VERSION 5.7 ;
  NOWIREEXTENSIONATPIN ON ;
  DIVIDERCHAR "/" ;
  BUSBITCHARS "[]" ;
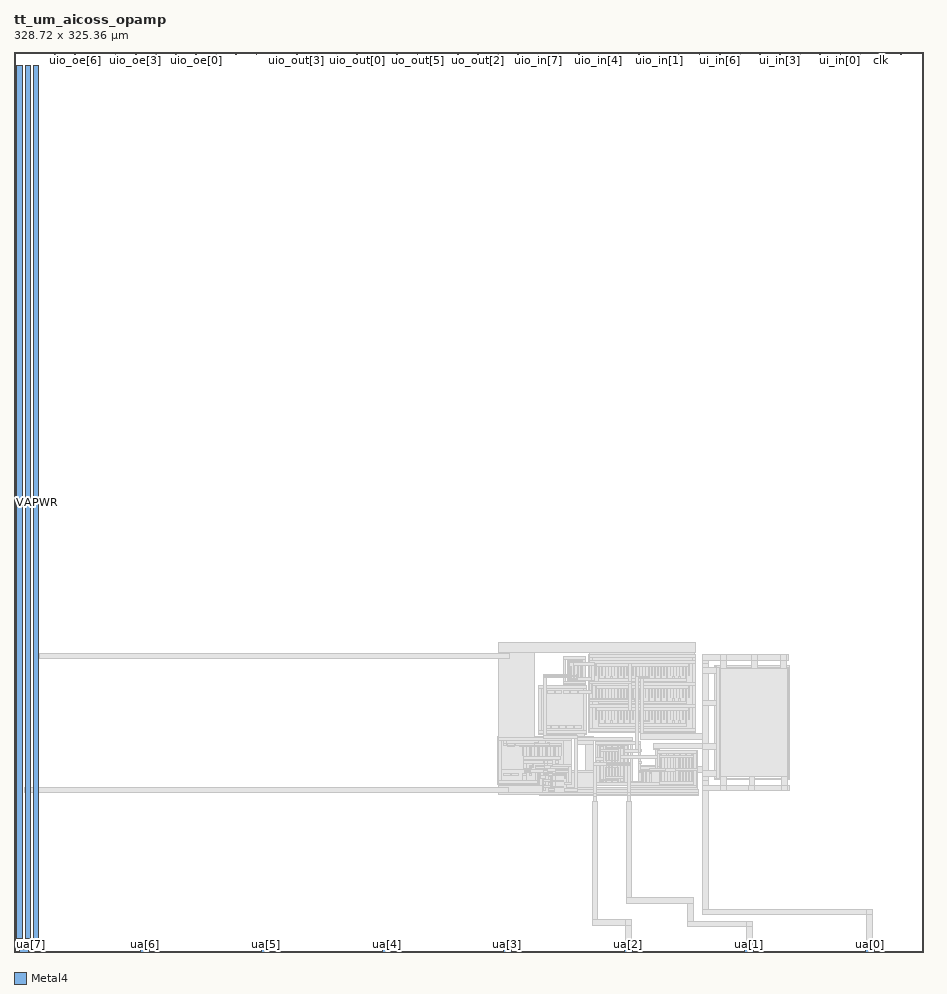
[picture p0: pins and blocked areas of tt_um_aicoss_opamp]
MACRO tt_um_aicoss_opamp
  CLASS BLOCK ;
  FOREIGN tt_um_aicoss_opamp ;
  ORIGIN 0.000 0.000 ;
  SIZE 328.720 BY 325.360 ;
  PIN clk
    DIRECTION INPUT ;
    USE SIGNAL ;
    PORT
      LAYER Metal4 ;
        RECT 313.170 324.360 313.470 325.360 ;
    END
  END clk
  PIN ena
    DIRECTION INPUT ;
    USE SIGNAL ;
    PORT
      LAYER Metal4 ;
        RECT 320.450 324.360 320.750 325.360 ;
    END
  END ena
  PIN rst_n
    DIRECTION INPUT ;
    USE SIGNAL ;
    PORT
      LAYER Metal4 ;
        RECT 305.890 324.360 306.190 325.360 ;
    END
  END rst_n
  PIN ua[0]
    DIRECTION INOUT ;
    USE SIGNAL ;
    ANTENNADIFFAREA 79.559998 ;
    PORT
      LAYER Metal4 ;
        RECT 307.900 0.000 310.900 1.000 ;
    END
  END ua[0]
  PIN ua[1]
    DIRECTION INOUT ;
    USE SIGNAL ;
    ANTENNAGATEAREA 7.200000 ;
    PORT
      LAYER Metal4 ;
        RECT 264.220 0.000 267.220 1.000 ;
    END
  END ua[1]
  PIN ua[2]
    DIRECTION INOUT ;
    USE SIGNAL ;
    ANTENNAGATEAREA 7.200000 ;
    PORT
      LAYER Metal4 ;
        RECT 220.540 0.000 223.540 1.000 ;
    END
  END ua[2]
  PIN ua[3]
    DIRECTION INOUT ;
    USE SIGNAL ;
    PORT
      LAYER Metal4 ;
        RECT 176.860 0.000 179.860 1.000 ;
    END
  END ua[3]
  PIN ua[4]
    DIRECTION INOUT ;
    USE SIGNAL ;
    PORT
      LAYER Metal4 ;
        RECT 133.180 0.000 136.180 1.000 ;
    END
  END ua[4]
  PIN ua[5]
    DIRECTION INOUT ;
    USE SIGNAL ;
    PORT
      LAYER Metal4 ;
        RECT 89.500 0.000 92.500 1.000 ;
    END
  END ua[5]
  PIN ua[6]
    DIRECTION INOUT ;
    USE SIGNAL ;
    PORT
      LAYER Metal4 ;
        RECT 45.820 0.000 48.820 1.000 ;
    END
  END ua[6]
  PIN ua[7]
    DIRECTION INOUT ;
    USE SIGNAL ;
    PORT
      LAYER Metal4 ;
        RECT 2.140 0.000 5.140 1.000 ;
    END
  END ua[7]
  PIN ui_in[0]
    DIRECTION INPUT ;
    USE SIGNAL ;
    PORT
      LAYER Metal4 ;
        RECT 298.610 324.360 298.910 325.360 ;
    END
  END ui_in[0]
  PIN ui_in[1]
    DIRECTION INPUT ;
    USE SIGNAL ;
    PORT
      LAYER Metal4 ;
        RECT 291.330 324.360 291.630 325.360 ;
    END
  END ui_in[1]
  PIN ui_in[2]
    DIRECTION INPUT ;
    USE SIGNAL ;
    PORT
      LAYER Metal4 ;
        RECT 284.050 324.360 284.350 325.360 ;
    END
  END ui_in[2]
  PIN ui_in[3]
    DIRECTION INPUT ;
    USE SIGNAL ;
    PORT
      LAYER Metal4 ;
        RECT 276.770 324.360 277.070 325.360 ;
    END
  END ui_in[3]
  PIN ui_in[4]
    DIRECTION INPUT ;
    USE SIGNAL ;
    PORT
      LAYER Metal4 ;
        RECT 269.490 324.360 269.790 325.360 ;
    END
  END ui_in[4]
  PIN ui_in[5]
    DIRECTION INPUT ;
    USE SIGNAL ;
    PORT
      LAYER Metal4 ;
        RECT 262.210 324.360 262.510 325.360 ;
    END
  END ui_in[5]
  PIN ui_in[6]
    DIRECTION INPUT ;
    USE SIGNAL ;
    PORT
      LAYER Metal4 ;
        RECT 254.930 324.360 255.230 325.360 ;
    END
  END ui_in[6]
  PIN ui_in[7]
    DIRECTION INPUT ;
    USE SIGNAL ;
    PORT
      LAYER Metal4 ;
        RECT 247.650 324.360 247.950 325.360 ;
    END
  END ui_in[7]
  PIN uio_in[0]
    DIRECTION INPUT ;
    USE SIGNAL ;
    PORT
      LAYER Metal4 ;
        RECT 240.370 324.360 240.670 325.360 ;
    END
  END uio_in[0]
  PIN uio_in[1]
    DIRECTION INPUT ;
    USE SIGNAL ;
    PORT
      LAYER Metal4 ;
        RECT 233.090 324.360 233.390 325.360 ;
    END
  END uio_in[1]
  PIN uio_in[2]
    DIRECTION INPUT ;
    USE SIGNAL ;
    PORT
      LAYER Metal4 ;
        RECT 225.810 324.360 226.110 325.360 ;
    END
  END uio_in[2]
  PIN uio_in[3]
    DIRECTION INPUT ;
    USE SIGNAL ;
    PORT
      LAYER Metal4 ;
        RECT 218.530 324.360 218.830 325.360 ;
    END
  END uio_in[3]
  PIN uio_in[4]
    DIRECTION INPUT ;
    USE SIGNAL ;
    PORT
      LAYER Metal4 ;
        RECT 211.250 324.360 211.550 325.360 ;
    END
  END uio_in[4]
  PIN uio_in[5]
    DIRECTION INPUT ;
    USE SIGNAL ;
    PORT
      LAYER Metal4 ;
        RECT 203.970 324.360 204.270 325.360 ;
    END
  END uio_in[5]
  PIN uio_in[6]
    DIRECTION INPUT ;
    USE SIGNAL ;
    PORT
      LAYER Metal4 ;
        RECT 196.690 324.360 196.990 325.360 ;
    END
  END uio_in[6]
  PIN uio_in[7]
    DIRECTION INPUT ;
    USE SIGNAL ;
    PORT
      LAYER Metal4 ;
        RECT 189.410 324.360 189.710 325.360 ;
    END
  END uio_in[7]
  PIN uio_oe[0]
    DIRECTION OUTPUT ;
    USE SIGNAL ;
    PORT
      LAYER Metal4 ;
        RECT 65.650 324.360 65.950 325.360 ;
    END
  END uio_oe[0]
  PIN uio_oe[1]
    DIRECTION OUTPUT ;
    USE SIGNAL ;
    PORT
      LAYER Metal4 ;
        RECT 58.370 324.360 58.670 325.360 ;
    END
  END uio_oe[1]
  PIN uio_oe[2]
    DIRECTION OUTPUT ;
    USE SIGNAL ;
    PORT
      LAYER Metal4 ;
        RECT 51.090 324.360 51.390 325.360 ;
    END
  END uio_oe[2]
  PIN uio_oe[3]
    DIRECTION OUTPUT ;
    USE SIGNAL ;
    PORT
      LAYER Metal4 ;
        RECT 43.810 324.360 44.110 325.360 ;
    END
  END uio_oe[3]
  PIN uio_oe[4]
    DIRECTION OUTPUT ;
    USE SIGNAL ;
    PORT
      LAYER Metal4 ;
        RECT 36.530 324.360 36.830 325.360 ;
    END
  END uio_oe[4]
  PIN uio_oe[5]
    DIRECTION OUTPUT ;
    USE SIGNAL ;
    PORT
      LAYER Metal4 ;
        RECT 29.250 324.360 29.550 325.360 ;
    END
  END uio_oe[5]
  PIN uio_oe[6]
    DIRECTION OUTPUT ;
    USE SIGNAL ;
    PORT
      LAYER Metal4 ;
        RECT 21.970 324.360 22.270 325.360 ;
    END
  END uio_oe[6]
  PIN uio_oe[7]
    DIRECTION OUTPUT ;
    USE SIGNAL ;
    PORT
      LAYER Metal4 ;
        RECT 14.690 324.360 14.990 325.360 ;
    END
  END uio_oe[7]
  PIN uio_out[0]
    DIRECTION OUTPUT ;
    USE SIGNAL ;
    PORT
      LAYER Metal4 ;
        RECT 123.890 324.360 124.190 325.360 ;
    END
  END uio_out[0]
  PIN uio_out[1]
    DIRECTION OUTPUT ;
    USE SIGNAL ;
    PORT
      LAYER Metal4 ;
        RECT 116.610 324.360 116.910 325.360 ;
    END
  END uio_out[1]
  PIN uio_out[2]
    DIRECTION OUTPUT ;
    USE SIGNAL ;
    PORT
      LAYER Metal4 ;
        RECT 109.330 324.360 109.630 325.360 ;
    END
  END uio_out[2]
  PIN uio_out[3]
    DIRECTION OUTPUT ;
    USE SIGNAL ;
    PORT
      LAYER Metal4 ;
        RECT 102.050 324.360 102.350 325.360 ;
    END
  END uio_out[3]
  PIN uio_out[4]
    DIRECTION OUTPUT ;
    USE SIGNAL ;
    PORT
      LAYER Metal4 ;
        RECT 94.770 324.360 95.070 325.360 ;
    END
  END uio_out[4]
  PIN uio_out[5]
    DIRECTION OUTPUT ;
    USE SIGNAL ;
    PORT
      LAYER Metal4 ;
        RECT 87.490 324.360 87.790 325.360 ;
    END
  END uio_out[5]
  PIN uio_out[6]
    DIRECTION OUTPUT ;
    USE SIGNAL ;
    PORT
      LAYER Metal4 ;
        RECT 80.210 324.360 80.510 325.360 ;
    END
  END uio_out[6]
  PIN uio_out[7]
    DIRECTION OUTPUT ;
    USE SIGNAL ;
    PORT
      LAYER Metal4 ;
        RECT 72.930 324.360 73.230 325.360 ;
    END
  END uio_out[7]
  PIN uo_out[0]
    DIRECTION OUTPUT ;
    USE SIGNAL ;
    PORT
      LAYER Metal4 ;
        RECT 182.130 324.360 182.430 325.360 ;
    END
  END uo_out[0]
  PIN uo_out[1]
    DIRECTION OUTPUT ;
    USE SIGNAL ;
    PORT
      LAYER Metal4 ;
        RECT 174.850 324.360 175.150 325.360 ;
    END
  END uo_out[1]
  PIN uo_out[2]
    DIRECTION OUTPUT ;
    USE SIGNAL ;
    PORT
      LAYER Metal4 ;
        RECT 167.570 324.360 167.870 325.360 ;
    END
  END uo_out[2]
  PIN uo_out[3]
    DIRECTION OUTPUT ;
    USE SIGNAL ;
    PORT
      LAYER Metal4 ;
        RECT 160.290 324.360 160.590 325.360 ;
    END
  END uo_out[3]
  PIN uo_out[4]
    DIRECTION OUTPUT ;
    USE SIGNAL ;
    PORT
      LAYER Metal4 ;
        RECT 153.010 324.360 153.310 325.360 ;
    END
  END uo_out[4]
  PIN uo_out[5]
    DIRECTION OUTPUT ;
    USE SIGNAL ;
    PORT
      LAYER Metal4 ;
        RECT 145.730 324.360 146.030 325.360 ;
    END
  END uo_out[5]
  PIN uo_out[6]
    DIRECTION OUTPUT ;
    USE SIGNAL ;
    PORT
      LAYER Metal4 ;
        RECT 138.450 324.360 138.750 325.360 ;
    END
  END uo_out[6]
  PIN uo_out[7]
    DIRECTION OUTPUT ;
    USE SIGNAL ;
    PORT
      LAYER Metal4 ;
        RECT 131.170 324.360 131.470 325.360 ;
    END
  END uo_out[7]
  PIN VDPWR
    DIRECTION INOUT ;
    USE POWER ;
    PORT
      LAYER Metal4 ;
        RECT 1.000 5.000 3.000 320.360 ;
    END
  END VDPWR
  PIN VGND
    DIRECTION INOUT ;
    USE GROUND ;
    PORT
      LAYER Metal4 ;
        RECT 4.000 5.000 6.000 320.360 ;
    END
  END VGND
  PIN VAPWR
    DIRECTION INOUT ;
    USE POWER ;
    PORT
      LAYER Metal4 ;
        RECT 7.000 5.000 9.000 320.360 ;
    END
  END VAPWR
  OBS
      LAYER Nwell ;
        RECT 199.980 98.230 204.980 105.380 ;
      LAYER Pwell ;
        RECT 189.500 78.700 207.060 96.480 ;
      LAYER Nwell ;
        RECT 207.800 79.450 246.420 107.560 ;
        RECT 174.950 66.150 200.000 77.750 ;
        RECT 174.950 60.700 189.570 66.150 ;
      LAYER Pwell ;
        RECT 193.950 65.900 200.900 65.950 ;
        RECT 189.950 64.350 200.900 65.900 ;
        RECT 189.950 63.700 201.200 64.350 ;
      LAYER Nwell ;
        RECT 174.950 60.650 189.500 60.700 ;
      LAYER Pwell ;
        RECT 189.950 56.600 200.900 63.700 ;
      LAYER Nwell ;
        RECT 210.330 60.030 222.030 75.730 ;
      LAYER Pwell ;
        RECT 225.650 60.000 231.670 67.270 ;
        RECT 232.200 58.900 246.950 72.900 ;
      LAYER Metal1 ;
        RECT 175.200 108.350 246.200 111.850 ;
        RECT 175.200 77.475 188.250 108.350 ;
        RECT 208.000 107.375 245.900 108.350 ;
        RECT 198.515 105.875 206.615 106.905 ;
        RECT 198.515 97.695 199.545 105.875 ;
        RECT 200.315 104.535 204.765 105.065 ;
        RECT 200.315 99.045 200.845 104.535 ;
        RECT 202.300 104.130 202.800 104.150 ;
        RECT 202.280 103.650 202.800 104.130 ;
        RECT 202.280 103.630 202.780 103.650 ;
        RECT 201.305 100.180 201.535 103.230 ;
        RECT 202.425 100.230 202.655 103.630 ;
        RECT 203.545 100.180 203.775 103.230 ;
        RECT 201.230 99.045 201.535 100.180 ;
        RECT 201.830 99.480 203.230 99.980 ;
        RECT 202.425 99.045 202.655 99.080 ;
        RECT 203.530 99.045 203.830 100.180 ;
        RECT 204.235 99.045 204.765 104.535 ;
        RECT 200.315 98.515 204.765 99.045 ;
        RECT 205.585 97.695 206.615 105.875 ;
        RECT 198.515 96.900 206.615 97.695 ;
        RECT 198.500 96.665 206.615 96.900 ;
        RECT 207.985 106.345 246.235 107.375 ;
        RECT 207.985 105.300 209.015 106.345 ;
        RECT 245.205 105.300 246.235 106.345 ;
        RECT 207.985 104.300 246.235 105.300 ;
        RECT 207.985 97.300 209.015 104.300 ;
        RECT 210.295 100.010 210.525 104.300 ;
        RECT 210.850 103.300 212.250 103.800 ;
        RECT 211.415 99.700 211.645 102.990 ;
        RECT 212.535 100.010 212.765 104.300 ;
        RECT 213.090 103.300 214.490 103.800 ;
        RECT 213.655 99.700 213.885 102.990 ;
        RECT 214.775 100.010 215.005 104.300 ;
        RECT 215.330 103.300 216.730 103.800 ;
        RECT 215.895 99.700 216.125 102.990 ;
        RECT 217.015 100.010 217.245 104.300 ;
        RECT 217.570 103.300 218.970 103.800 ;
        RECT 218.135 99.700 218.365 102.990 ;
        RECT 219.255 100.010 219.485 104.300 ;
        RECT 219.810 103.300 221.210 103.800 ;
        RECT 220.375 99.700 220.605 102.990 ;
        RECT 221.495 100.010 221.725 104.300 ;
        RECT 222.050 103.300 223.450 103.800 ;
        RECT 222.615 99.700 222.845 102.990 ;
        RECT 223.735 100.010 223.965 104.300 ;
        RECT 224.290 103.300 225.690 103.800 ;
        RECT 224.855 99.700 225.085 102.990 ;
        RECT 225.975 100.010 226.205 104.300 ;
        RECT 226.530 103.300 227.930 103.800 ;
        RECT 227.095 99.700 227.325 102.990 ;
        RECT 228.215 100.010 228.445 104.300 ;
        RECT 228.770 103.300 230.170 103.800 ;
        RECT 229.335 99.700 229.565 102.990 ;
        RECT 230.455 100.010 230.685 104.300 ;
        RECT 231.010 103.300 232.410 103.800 ;
        RECT 231.575 99.700 231.805 102.990 ;
        RECT 232.695 100.010 232.925 104.300 ;
        RECT 233.250 103.300 234.650 103.800 ;
        RECT 233.815 99.700 234.045 102.990 ;
        RECT 234.935 100.010 235.165 104.300 ;
        RECT 235.490 103.300 236.890 103.800 ;
        RECT 236.055 99.700 236.285 102.990 ;
        RECT 237.175 100.010 237.405 104.300 ;
        RECT 237.730 103.300 239.130 103.800 ;
        RECT 238.295 99.700 238.525 102.990 ;
        RECT 239.415 100.010 239.645 104.300 ;
        RECT 239.970 103.300 241.370 103.800 ;
        RECT 240.535 99.700 240.765 102.990 ;
        RECT 241.655 100.010 241.885 104.300 ;
        RECT 242.210 103.300 243.610 103.800 ;
        RECT 242.775 99.700 243.005 102.990 ;
        RECT 243.895 100.010 244.125 104.300 ;
        RECT 211.300 98.700 211.800 99.700 ;
        RECT 213.500 98.700 214.000 99.700 ;
        RECT 215.750 98.700 216.250 99.700 ;
        RECT 218.000 98.700 218.500 99.700 ;
        RECT 220.250 98.700 220.750 99.700 ;
        RECT 222.500 98.700 223.000 99.700 ;
        RECT 224.700 99.200 225.200 99.700 ;
        RECT 226.950 98.700 227.450 99.700 ;
        RECT 229.200 99.200 229.700 99.700 ;
        RECT 231.450 98.700 231.950 99.700 ;
        RECT 233.700 98.700 234.200 99.700 ;
        RECT 235.900 98.700 236.400 99.700 ;
        RECT 238.150 98.700 238.650 99.700 ;
        RECT 240.400 98.700 240.900 99.700 ;
        RECT 242.650 98.700 243.150 99.700 ;
        RECT 211.300 97.700 243.150 98.700 ;
        RECT 245.205 97.300 246.235 104.300 ;
        RECT 198.500 96.295 206.600 96.665 ;
        RECT 207.985 96.300 246.235 97.300 ;
        RECT 189.685 95.265 206.875 96.295 ;
        RECT 189.685 79.915 190.715 95.265 ;
        RECT 196.250 94.435 197.400 94.450 ;
        RECT 198.850 94.435 200.000 94.450 ;
        RECT 191.490 93.405 192.470 94.435 ;
        RECT 192.890 94.400 193.870 94.435 ;
        RECT 194.290 94.400 195.270 94.435 ;
        RECT 192.890 93.405 195.270 94.400 ;
        RECT 195.690 93.450 198.070 94.435 ;
        RECT 195.690 93.405 196.670 93.450 ;
        RECT 197.090 93.405 198.070 93.450 ;
        RECT 198.490 93.450 200.870 94.435 ;
        RECT 198.490 93.405 199.470 93.450 ;
        RECT 199.890 93.405 200.870 93.450 ;
        RECT 201.290 94.400 202.270 94.435 ;
        RECT 202.690 94.400 203.670 94.435 ;
        RECT 201.290 93.405 203.670 94.400 ;
        RECT 204.090 93.405 205.070 94.435 ;
        RECT 193.450 93.400 194.600 93.405 ;
        RECT 201.900 93.400 203.050 93.405 ;
        RECT 200.450 81.775 201.600 81.800 ;
        RECT 203.150 81.775 204.300 81.800 ;
        RECT 191.490 81.750 192.470 81.775 ;
        RECT 192.890 81.750 193.870 81.775 ;
        RECT 191.490 80.750 193.870 81.750 ;
        RECT 191.490 80.745 192.470 80.750 ;
        RECT 192.890 80.745 193.870 80.750 ;
        RECT 194.290 81.750 195.270 81.775 ;
        RECT 195.690 81.750 196.670 81.775 ;
        RECT 194.290 80.750 196.670 81.750 ;
        RECT 194.290 80.745 195.270 80.750 ;
        RECT 195.690 80.745 196.670 80.750 ;
        RECT 197.090 81.750 198.070 81.775 ;
        RECT 198.490 81.750 199.470 81.775 ;
        RECT 197.090 80.750 199.470 81.750 ;
        RECT 197.090 80.745 198.070 80.750 ;
        RECT 198.490 80.745 199.470 80.750 ;
        RECT 199.890 80.800 202.270 81.775 ;
        RECT 199.890 80.745 200.870 80.800 ;
        RECT 201.290 80.745 202.270 80.800 ;
        RECT 202.690 80.800 205.070 81.775 ;
        RECT 202.690 80.745 203.670 80.800 ;
        RECT 204.090 80.745 205.070 80.800 ;
        RECT 205.845 79.915 206.875 95.265 ;
        RECT 189.685 78.885 206.875 79.915 ;
        RECT 207.985 89.300 209.015 96.300 ;
        RECT 210.295 92.010 210.525 96.300 ;
        RECT 210.850 95.300 212.250 95.800 ;
        RECT 211.415 91.700 211.645 94.990 ;
        RECT 212.535 92.010 212.765 96.300 ;
        RECT 213.090 95.300 214.490 95.800 ;
        RECT 213.655 91.700 213.885 94.990 ;
        RECT 214.775 92.010 215.005 96.300 ;
        RECT 215.330 95.300 216.730 95.800 ;
        RECT 215.895 91.700 216.125 94.990 ;
        RECT 217.015 92.010 217.245 96.300 ;
        RECT 217.570 95.300 218.970 95.800 ;
        RECT 218.135 91.700 218.365 94.990 ;
        RECT 219.255 92.010 219.485 96.300 ;
        RECT 219.810 95.300 221.210 95.800 ;
        RECT 220.375 91.700 220.605 94.990 ;
        RECT 221.495 92.010 221.725 96.300 ;
        RECT 222.050 95.300 223.450 95.800 ;
        RECT 222.615 91.700 222.845 94.990 ;
        RECT 223.735 92.010 223.965 96.300 ;
        RECT 224.290 95.300 225.690 95.800 ;
        RECT 224.855 91.700 225.085 94.990 ;
        RECT 225.975 92.010 226.205 96.300 ;
        RECT 226.530 95.300 227.930 95.800 ;
        RECT 227.095 91.700 227.325 94.990 ;
        RECT 228.215 92.010 228.445 96.300 ;
        RECT 228.770 95.300 230.170 95.800 ;
        RECT 229.335 91.700 229.565 94.990 ;
        RECT 230.455 92.010 230.685 96.300 ;
        RECT 231.010 95.300 232.410 95.800 ;
        RECT 231.575 91.700 231.805 94.990 ;
        RECT 232.695 92.010 232.925 96.300 ;
        RECT 233.250 95.300 234.650 95.800 ;
        RECT 233.815 91.700 234.045 94.990 ;
        RECT 234.935 92.010 235.165 96.300 ;
        RECT 235.490 95.300 236.890 95.800 ;
        RECT 236.055 91.700 236.285 94.990 ;
        RECT 237.175 92.010 237.405 96.300 ;
        RECT 237.730 95.300 239.130 95.800 ;
        RECT 238.295 91.700 238.525 94.990 ;
        RECT 239.415 92.010 239.645 96.300 ;
        RECT 239.970 95.300 241.370 95.800 ;
        RECT 240.535 91.700 240.765 94.990 ;
        RECT 241.655 92.010 241.885 96.300 ;
        RECT 242.210 95.300 243.610 95.800 ;
        RECT 242.775 91.700 243.005 94.990 ;
        RECT 243.895 92.010 244.125 96.300 ;
        RECT 211.300 90.700 211.800 91.700 ;
        RECT 213.500 90.700 214.000 91.700 ;
        RECT 215.750 90.700 216.250 91.700 ;
        RECT 218.000 90.700 218.500 91.700 ;
        RECT 220.250 90.700 220.750 91.700 ;
        RECT 222.500 90.700 223.000 91.700 ;
        RECT 224.700 90.700 225.200 91.700 ;
        RECT 226.950 91.200 227.450 91.700 ;
        RECT 229.200 90.700 229.700 91.700 ;
        RECT 231.450 90.700 231.950 91.700 ;
        RECT 233.700 90.700 234.200 91.700 ;
        RECT 235.900 90.700 236.400 91.700 ;
        RECT 238.150 90.700 238.650 91.700 ;
        RECT 240.400 90.700 240.900 91.700 ;
        RECT 242.650 90.700 243.150 91.700 ;
        RECT 211.300 89.700 243.150 90.700 ;
        RECT 245.205 89.300 246.235 96.300 ;
        RECT 207.985 88.300 246.235 89.300 ;
        RECT 207.985 80.665 209.015 88.300 ;
        RECT 210.295 84.010 210.525 88.300 ;
        RECT 210.850 87.300 212.250 87.800 ;
        RECT 211.415 83.700 211.645 86.990 ;
        RECT 212.535 84.010 212.765 88.300 ;
        RECT 213.090 87.300 214.490 87.800 ;
        RECT 213.655 83.700 213.885 86.990 ;
        RECT 214.775 84.010 215.005 88.300 ;
        RECT 215.330 87.300 216.730 87.800 ;
        RECT 215.895 83.700 216.125 86.990 ;
        RECT 217.015 84.010 217.245 88.300 ;
        RECT 217.570 87.300 218.970 87.800 ;
        RECT 218.135 83.700 218.365 86.990 ;
        RECT 219.255 84.010 219.485 88.300 ;
        RECT 219.810 87.300 221.210 87.800 ;
        RECT 220.375 83.700 220.605 86.990 ;
        RECT 221.495 84.010 221.725 88.300 ;
        RECT 222.050 87.300 223.450 87.800 ;
        RECT 222.615 83.700 222.845 86.990 ;
        RECT 223.735 84.010 223.965 88.300 ;
        RECT 224.290 87.300 225.690 87.800 ;
        RECT 224.855 83.700 225.085 86.990 ;
        RECT 225.975 84.010 226.205 88.300 ;
        RECT 226.530 87.300 227.930 87.800 ;
        RECT 227.095 83.700 227.325 86.990 ;
        RECT 228.215 84.010 228.445 88.300 ;
        RECT 228.770 87.300 230.170 87.800 ;
        RECT 229.335 83.700 229.565 86.990 ;
        RECT 230.455 84.010 230.685 88.300 ;
        RECT 231.010 87.300 232.410 87.800 ;
        RECT 231.575 83.700 231.805 86.990 ;
        RECT 232.695 84.010 232.925 88.300 ;
        RECT 233.250 87.300 234.650 87.800 ;
        RECT 233.815 83.700 234.045 86.990 ;
        RECT 234.935 84.010 235.165 88.300 ;
        RECT 235.490 87.300 236.890 87.800 ;
        RECT 236.055 83.700 236.285 86.990 ;
        RECT 237.175 84.010 237.405 88.300 ;
        RECT 237.730 87.300 239.130 87.800 ;
        RECT 238.295 83.700 238.525 86.990 ;
        RECT 239.415 84.010 239.645 88.300 ;
        RECT 239.970 87.300 241.370 87.800 ;
        RECT 240.535 83.700 240.765 86.990 ;
        RECT 241.655 84.010 241.885 88.300 ;
        RECT 242.210 87.300 243.610 87.800 ;
        RECT 242.775 83.700 243.005 86.990 ;
        RECT 243.895 84.010 244.125 88.300 ;
        RECT 211.300 82.700 211.800 83.700 ;
        RECT 213.500 82.700 214.000 83.700 ;
        RECT 215.750 82.700 216.250 83.700 ;
        RECT 218.000 82.700 218.500 83.700 ;
        RECT 220.250 82.700 220.750 83.700 ;
        RECT 222.500 82.700 223.000 83.700 ;
        RECT 224.700 83.200 225.200 83.700 ;
        RECT 226.950 82.700 227.450 83.700 ;
        RECT 229.200 83.200 229.700 83.700 ;
        RECT 231.450 82.700 231.950 83.700 ;
        RECT 233.700 82.700 234.200 83.700 ;
        RECT 235.900 82.700 236.400 83.700 ;
        RECT 238.150 82.700 238.650 83.700 ;
        RECT 240.400 82.700 240.900 83.700 ;
        RECT 242.650 82.700 243.150 83.700 ;
        RECT 211.300 81.700 243.150 82.700 ;
        RECT 245.205 80.665 246.235 88.300 ;
        RECT 207.985 79.635 246.235 80.665 ;
        RECT 203.350 77.950 206.250 78.885 ;
        RECT 198.705 77.475 201.450 77.500 ;
        RECT 175.185 76.445 201.450 77.475 ;
        RECT 175.185 61.915 176.215 76.445 ;
        RECT 177.100 75.335 178.100 76.445 ;
        RECT 188.310 75.550 189.290 75.600 ;
        RECT 178.500 75.335 180.850 75.400 ;
        RECT 181.300 75.335 189.350 75.550 ;
        RECT 177.090 74.550 178.100 75.335 ;
        RECT 177.090 74.505 178.070 74.550 ;
        RECT 178.490 74.505 180.870 75.335 ;
        RECT 181.290 74.550 189.350 75.335 ;
        RECT 181.290 74.505 182.270 74.550 ;
        RECT 178.500 74.450 180.850 74.505 ;
        RECT 182.750 74.300 189.350 74.550 ;
        RECT 189.750 74.300 192.250 76.445 ;
        RECT 192.640 74.800 198.000 75.550 ;
        RECT 192.640 74.600 198.045 74.800 ;
        RECT 192.650 74.300 198.050 74.600 ;
        RECT 183.975 70.910 184.205 74.300 ;
        RECT 184.350 69.700 184.850 70.700 ;
        RECT 185.095 69.250 185.325 73.890 ;
        RECT 186.215 70.910 186.445 74.300 ;
        RECT 186.875 70.910 187.105 74.300 ;
        RECT 185.600 70.635 186.100 70.700 ;
        RECT 185.575 69.905 186.100 70.635 ;
        RECT 185.600 69.700 186.100 69.905 ;
        RECT 187.250 69.700 187.750 70.700 ;
        RECT 187.995 69.250 188.225 73.890 ;
        RECT 189.115 70.910 189.345 74.300 ;
        RECT 189.775 70.910 190.005 74.300 ;
        RECT 190.895 70.700 191.125 73.890 ;
        RECT 192.015 70.910 192.245 74.300 ;
        RECT 192.675 70.910 192.905 74.300 ;
        RECT 188.500 70.635 189.000 70.700 ;
        RECT 188.475 69.905 189.000 70.635 ;
        RECT 188.500 69.700 189.000 69.905 ;
        RECT 190.150 69.700 191.900 70.700 ;
        RECT 193.050 69.700 193.550 70.700 ;
        RECT 191.900 69.250 192.900 69.290 ;
        RECT 193.795 69.250 194.025 73.890 ;
        RECT 194.915 70.910 195.145 74.300 ;
        RECT 195.575 70.910 195.805 74.300 ;
        RECT 194.300 70.635 194.800 70.700 ;
        RECT 194.275 69.905 194.800 70.635 ;
        RECT 194.300 69.700 194.800 69.905 ;
        RECT 195.950 69.700 196.450 70.700 ;
        RECT 196.695 69.250 196.925 73.890 ;
        RECT 197.815 70.910 198.045 74.300 ;
        RECT 197.200 70.635 197.700 70.700 ;
        RECT 197.175 69.905 197.700 70.635 ;
        RECT 197.200 69.700 197.700 69.905 ;
        RECT 185.095 68.300 196.925 69.250 ;
        RECT 185.100 68.250 196.900 68.300 ;
        RECT 184.550 66.400 185.150 67.400 ;
        RECT 186.450 67.050 186.950 67.400 ;
        RECT 187.400 67.050 187.900 68.250 ;
        RECT 191.900 68.190 192.900 68.250 ;
        RECT 198.705 67.415 201.450 76.445 ;
        RECT 203.350 77.405 209.400 77.950 ;
        RECT 203.350 76.375 223.765 77.405 ;
        RECT 203.350 75.050 209.645 76.375 ;
        RECT 188.385 67.200 201.450 67.415 ;
        RECT 186.450 66.550 187.900 67.050 ;
        RECT 186.450 66.400 186.950 66.550 ;
        RECT 184.550 65.400 185.050 66.400 ;
        RECT 188.355 66.385 201.450 67.200 ;
        RECT 185.300 66.100 186.300 66.200 ;
        RECT 185.300 65.700 187.050 66.100 ;
        RECT 184.550 65.000 186.300 65.400 ;
        RECT 185.300 64.900 186.300 65.000 ;
        RECT 186.550 64.700 187.050 65.700 ;
        RECT 177.100 64.675 179.450 64.700 ;
        RECT 179.900 64.675 182.250 64.700 ;
        RECT 177.090 63.845 179.470 64.675 ;
        RECT 179.890 63.845 182.270 64.675 ;
        RECT 177.100 63.800 179.450 63.845 ;
        RECT 179.900 63.800 182.250 63.845 ;
        RECT 183.900 63.700 185.150 64.700 ;
        RECT 186.450 63.700 187.050 64.700 ;
        RECT 183.900 61.915 185.100 63.700 ;
        RECT 188.355 61.915 189.385 66.385 ;
        RECT 199.150 66.350 201.450 66.385 ;
        RECT 175.185 61.850 183.000 61.915 ;
        RECT 183.900 61.850 189.385 61.915 ;
        RECT 175.185 60.885 189.385 61.850 ;
        RECT 190.135 65.750 200.715 65.765 ;
        RECT 206.500 65.750 209.645 75.050 ;
        RECT 190.135 64.735 209.645 65.750 ;
        RECT 190.135 60.350 191.165 64.735 ;
        RECT 198.200 64.340 199.350 64.350 ;
        RECT 191.500 63.800 193.150 64.300 ;
        RECT 195.850 63.900 199.350 64.340 ;
        RECT 195.850 63.840 198.550 63.900 ;
        RECT 191.500 62.600 192.000 63.800 ;
        RECT 194.250 63.650 195.100 63.700 ;
        RECT 193.300 62.200 193.800 63.600 ;
        RECT 191.500 61.700 193.800 62.200 ;
        RECT 194.250 62.650 195.500 63.650 ;
        RECT 198.900 63.640 199.350 63.900 ;
        RECT 191.500 60.500 192.000 61.700 ;
        RECT 194.250 61.450 195.100 62.650 ;
        RECT 198.850 62.640 199.350 63.640 ;
        RECT 195.850 61.620 198.550 62.120 ;
        RECT 175.100 57.815 191.165 60.350 ;
        RECT 193.300 60.050 193.800 61.450 ;
        RECT 191.500 59.550 193.800 60.050 ;
        RECT 194.250 60.450 195.500 61.450 ;
        RECT 194.250 60.440 195.455 60.450 ;
        RECT 191.500 58.300 192.000 59.550 ;
        RECT 194.250 59.300 195.100 60.440 ;
        RECT 198.850 60.420 199.350 61.420 ;
        RECT 195.850 59.400 198.550 59.900 ;
        RECT 193.345 59.200 195.100 59.300 ;
        RECT 199.685 59.345 209.645 64.735 ;
        RECT 210.515 74.515 221.845 75.545 ;
        RECT 210.515 61.245 211.545 74.515 ;
        RECT 212.130 61.780 213.130 74.180 ;
        RECT 213.825 69.390 214.055 74.515 ;
        RECT 214.945 73.130 215.175 73.280 ;
        RECT 214.830 72.630 215.330 73.130 ;
        RECT 214.945 69.390 215.175 72.630 ;
        RECT 216.065 69.390 216.295 74.515 ;
        RECT 217.030 73.530 217.530 74.030 ;
        RECT 217.185 69.390 217.415 73.530 ;
        RECT 218.305 69.390 218.535 74.515 ;
        RECT 214.230 68.630 215.930 69.130 ;
        RECT 216.480 68.630 218.180 69.130 ;
        RECT 214.830 68.230 215.330 68.630 ;
        RECT 213.680 67.730 217.530 68.230 ;
        RECT 217.030 67.330 217.530 67.730 ;
        RECT 214.230 66.830 215.930 67.330 ;
        RECT 216.480 66.830 218.180 67.330 ;
        RECT 213.825 61.245 214.055 66.570 ;
        RECT 214.945 63.330 215.175 66.570 ;
        RECT 214.830 62.830 215.330 63.330 ;
        RECT 214.945 62.680 215.175 62.830 ;
        RECT 216.065 61.245 216.295 66.570 ;
        RECT 217.185 62.430 217.415 66.570 ;
        RECT 217.030 61.930 217.530 62.430 ;
        RECT 218.305 61.245 218.535 66.570 ;
        RECT 219.230 61.780 220.230 74.180 ;
        RECT 220.815 61.245 221.845 74.515 ;
        RECT 210.515 60.215 221.845 61.245 ;
        RECT 222.735 61.600 223.765 76.375 ;
        RECT 225.650 73.340 226.650 73.350 ;
        RECT 225.600 72.360 226.700 73.340 ;
        RECT 225.650 67.990 226.650 72.360 ;
        RECT 232.385 71.685 246.765 72.715 ;
        RECT 232.385 67.200 233.415 71.685 ;
        RECT 233.750 70.200 234.250 71.685 ;
        RECT 234.850 70.200 235.350 71.200 ;
        RECT 236.000 70.200 236.500 71.685 ;
        RECT 237.100 70.200 237.600 71.200 ;
        RECT 238.250 70.200 238.750 71.685 ;
        RECT 239.350 70.200 239.850 71.200 ;
        RECT 240.450 70.200 240.950 71.685 ;
        RECT 241.600 70.200 242.100 71.200 ;
        RECT 242.700 70.200 243.200 71.685 ;
        RECT 243.850 70.200 244.350 71.200 ;
        RECT 244.950 70.200 245.450 71.685 ;
        RECT 231.300 67.085 233.415 67.200 ;
        RECT 225.835 66.055 233.415 67.085 ;
        RECT 233.885 66.670 234.115 70.200 ;
        RECT 235.005 66.670 235.235 70.200 ;
        RECT 236.125 66.670 236.355 70.200 ;
        RECT 237.245 66.670 237.475 70.200 ;
        RECT 238.365 66.670 238.595 70.200 ;
        RECT 239.485 66.670 239.715 70.200 ;
        RECT 240.605 66.670 240.835 70.200 ;
        RECT 241.725 66.670 241.955 70.200 ;
        RECT 242.845 66.670 243.075 70.200 ;
        RECT 243.965 66.670 244.195 70.200 ;
        RECT 245.085 66.670 245.315 70.200 ;
        RECT 225.835 61.600 226.865 66.055 ;
        RECT 227.325 65.200 229.400 65.700 ;
        RECT 227.325 61.620 227.555 65.200 ;
        RECT 229.650 64.900 230.150 65.700 ;
        RECT 222.735 61.215 226.865 61.600 ;
        RECT 228.445 61.215 228.675 64.900 ;
        RECT 229.565 64.400 230.150 64.900 ;
        RECT 229.565 61.620 229.795 64.400 ;
        RECT 230.455 61.215 233.415 66.055 ;
        RECT 234.100 65.400 245.350 66.400 ;
        RECT 233.885 61.600 234.115 65.130 ;
        RECT 235.005 61.600 235.235 65.130 ;
        RECT 236.125 61.600 236.355 65.130 ;
        RECT 237.245 61.600 237.475 65.130 ;
        RECT 238.365 61.600 238.595 65.130 ;
        RECT 239.485 61.600 239.715 65.130 ;
        RECT 240.605 61.600 240.835 65.130 ;
        RECT 241.725 61.600 241.955 65.130 ;
        RECT 242.845 61.600 243.075 65.130 ;
        RECT 243.965 61.600 244.195 65.130 ;
        RECT 245.085 61.600 245.315 65.130 ;
        RECT 222.735 60.115 233.415 61.215 ;
        RECT 233.750 60.115 234.250 61.600 ;
        RECT 234.850 60.600 235.350 61.600 ;
        RECT 236.000 60.115 236.500 61.600 ;
        RECT 237.100 60.600 237.600 61.600 ;
        RECT 238.250 60.115 238.750 61.600 ;
        RECT 239.350 60.600 239.850 61.600 ;
        RECT 240.450 60.115 240.950 61.600 ;
        RECT 241.600 60.600 242.100 61.600 ;
        RECT 242.700 60.115 243.200 61.600 ;
        RECT 243.850 60.600 244.350 61.600 ;
        RECT 244.950 60.115 245.450 61.600 ;
        RECT 245.735 60.115 246.765 71.685 ;
        RECT 222.735 59.600 246.765 60.115 ;
        RECT 222.735 59.345 246.950 59.600 ;
        RECT 193.345 58.455 195.500 59.200 ;
        RECT 193.350 58.200 195.500 58.455 ;
        RECT 198.850 58.200 199.350 59.200 ;
        RECT 199.685 58.800 246.950 59.345 ;
        RECT 193.350 57.815 195.100 58.200 ;
        RECT 199.685 57.815 247.500 58.800 ;
        RECT 175.100 56.800 247.500 57.815 ;
        RECT 190.135 56.785 247.500 56.800 ;
        RECT 199.900 56.700 247.500 56.785 ;
        RECT 199.900 56.650 209.400 56.700 ;
      LAYER Metal2 ;
        RECT 176.950 108.000 178.950 108.050 ;
        RECT 176.900 106.000 179.000 108.000 ;
        RECT 176.950 105.950 178.950 106.000 ;
        RECT 202.300 103.650 202.800 104.150 ;
        RECT 210.400 103.300 244.010 104.300 ;
        RECT 191.500 100.000 200.700 100.300 ;
        RECT 191.500 99.500 203.200 100.000 ;
        RECT 191.500 99.300 200.700 99.500 ;
        RECT 191.500 78.300 192.500 99.300 ;
        RECT 224.700 99.200 229.700 99.700 ;
        RECT 203.750 98.200 209.000 99.200 ;
        RECT 224.700 98.700 225.700 99.200 ;
        RECT 204.100 93.400 205.050 94.500 ;
        RECT 208.000 91.700 209.000 98.200 ;
        RECT 226.650 97.700 227.650 98.700 ;
        RECT 210.400 95.300 244.010 96.300 ;
        RECT 208.000 91.200 227.450 91.700 ;
        RECT 208.000 90.700 224.150 91.200 ;
        RECT 226.650 89.700 227.650 90.700 ;
        RECT 210.400 87.300 244.010 88.300 ;
        RECT 224.700 83.200 229.700 83.700 ;
        RECT 224.700 82.700 225.700 83.200 ;
        RECT 226.650 81.700 227.650 82.700 ;
        RECT 191.500 77.300 203.550 78.300 ;
        RECT 192.690 75.550 193.690 75.610 ;
        RECT 188.250 74.550 193.690 75.550 ;
        RECT 192.690 74.490 193.690 74.550 ;
        RECT 184.350 70.650 184.850 70.700 ;
        RECT 185.600 70.650 186.100 70.700 ;
        RECT 187.250 70.650 187.750 70.700 ;
        RECT 188.500 70.650 189.000 70.700 ;
        RECT 190.150 70.650 190.650 70.700 ;
        RECT 191.400 70.650 191.900 70.700 ;
        RECT 193.050 70.650 193.550 70.700 ;
        RECT 194.300 70.650 194.800 70.700 ;
        RECT 195.950 70.650 196.450 70.700 ;
        RECT 197.200 70.650 197.700 70.700 ;
        RECT 184.350 69.650 197.700 70.650 ;
        RECT 190.500 69.250 191.500 69.650 ;
        RECT 184.100 68.250 191.500 69.250 ;
        RECT 184.150 66.400 185.150 68.250 ;
        RECT 191.840 68.240 192.960 69.240 ;
        RECT 191.900 67.350 192.900 68.240 ;
        RECT 194.750 67.950 195.750 69.650 ;
        RECT 191.900 66.400 193.800 67.350 ;
        RECT 194.750 66.950 201.500 67.950 ;
        RECT 191.900 66.350 195.800 66.400 ;
        RECT 186.550 64.900 191.400 65.900 ;
        RECT 192.800 65.400 195.800 66.350 ;
        RECT 190.400 63.650 191.400 64.900 ;
        RECT 194.800 64.350 195.800 65.400 ;
        RECT 194.800 64.340 196.300 64.350 ;
        RECT 194.800 63.840 198.550 64.340 ;
        RECT 190.400 62.650 192.000 63.650 ;
        RECT 194.800 62.150 195.650 63.840 ;
        RECT 198.850 62.640 199.350 63.640 ;
        RECT 194.800 62.120 196.300 62.150 ;
        RECT 194.800 61.620 198.550 62.120 ;
        RECT 194.800 59.900 195.650 61.620 ;
        RECT 200.500 61.450 201.500 66.950 ;
        RECT 198.900 61.420 201.500 61.450 ;
        RECT 198.850 60.450 201.500 61.420 ;
        RECT 198.850 60.420 199.350 60.450 ;
        RECT 176.650 59.550 178.650 59.600 ;
        RECT 176.600 57.550 178.700 59.550 ;
        RECT 194.800 59.400 198.550 59.900 ;
        RECT 202.550 59.200 203.550 77.300 ;
        RECT 210.100 75.050 226.650 76.050 ;
        RECT 210.100 70.400 211.100 75.050 ;
        RECT 213.680 73.530 220.230 74.030 ;
        RECT 212.130 72.630 218.680 73.130 ;
        RECT 220.850 72.300 221.850 73.300 ;
        RECT 225.650 72.300 226.650 75.050 ;
        RECT 231.260 73.410 233.340 75.390 ;
        RECT 231.800 70.950 232.800 73.410 ;
        RECT 210.100 69.400 213.150 70.400 ;
        RECT 219.250 69.950 232.800 70.950 ;
        RECT 233.500 70.200 245.600 71.200 ;
        RECT 213.280 68.450 214.280 68.480 ;
        RECT 198.850 58.200 203.550 59.200 ;
        RECT 209.500 67.480 214.280 68.450 ;
        RECT 217.030 68.230 217.530 69.130 ;
        RECT 218.150 68.480 222.850 68.500 ;
        RECT 218.130 68.230 222.850 68.480 ;
        RECT 214.780 67.730 222.850 68.230 ;
        RECT 225.590 68.040 226.710 69.040 ;
        RECT 209.500 67.450 214.250 67.480 ;
        RECT 176.650 57.500 178.650 57.550 ;
        RECT 209.500 56.300 210.500 67.450 ;
        RECT 214.780 66.830 215.280 67.730 ;
        RECT 218.130 67.500 222.850 67.730 ;
        RECT 218.130 67.480 219.130 67.500 ;
        RECT 213.680 62.830 220.230 63.330 ;
        RECT 212.130 61.930 218.680 62.430 ;
        RECT 221.850 56.700 222.850 67.500 ;
        RECT 225.650 65.700 226.650 68.040 ;
        RECT 231.800 66.400 232.800 69.950 ;
        RECT 239.100 66.425 240.050 70.200 ;
        RECT 247.100 66.900 249.100 66.950 ;
        RECT 247.100 66.425 251.100 66.900 ;
        RECT 229.700 65.700 235.350 66.400 ;
        RECT 225.650 65.200 228.700 65.700 ;
        RECT 229.650 65.400 235.350 65.700 ;
        RECT 239.100 65.475 251.100 66.425 ;
        RECT 225.650 65.000 226.650 65.200 ;
        RECT 229.650 64.900 230.500 65.400 ;
        RECT 229.650 64.400 230.150 64.900 ;
        RECT 239.100 61.600 240.050 65.475 ;
        RECT 247.100 64.900 251.100 65.475 ;
        RECT 247.100 64.850 249.100 64.900 ;
        RECT 233.500 60.600 245.600 61.600 ;
      LAYER Metal3 ;
        RECT 7.000 108.000 9.000 108.050 ;
        RECT 7.000 106.000 179.000 108.000 ;
        RECT 249.045 107.500 252.555 107.505 ;
        RECT 255.550 107.500 257.550 107.550 ;
        RECT 266.650 107.500 268.650 107.550 ;
        RECT 277.250 107.500 279.250 107.550 ;
        RECT 7.000 105.950 9.000 106.000 ;
        RECT 249.045 105.500 280.150 107.500 ;
        RECT 249.045 105.490 252.555 105.500 ;
        RECT 202.100 103.650 209.750 104.650 ;
        RECT 208.750 98.050 209.750 103.650 ;
        RECT 207.950 97.950 209.750 98.050 ;
        RECT 222.250 97.950 223.250 104.300 ;
        RECT 249.045 101.845 251.060 105.490 ;
        RECT 255.550 105.450 257.550 105.500 ;
        RECT 266.650 105.450 268.650 105.500 ;
        RECT 277.250 105.450 279.250 105.500 ;
        RECT 207.950 96.950 223.250 97.950 ;
        RECT 207.950 94.500 208.950 96.950 ;
        RECT 204.100 93.500 208.950 94.500 ;
        RECT 204.100 93.400 205.050 93.500 ;
        RECT 222.250 87.300 223.250 96.950 ;
        RECT 224.700 73.300 225.700 99.700 ;
        RECT 226.650 78.950 227.650 98.700 ;
        RECT 249.050 78.950 251.050 101.845 ;
        RECT 226.650 76.950 251.050 78.950 ;
        RECT 226.650 76.750 227.650 76.950 ;
        RECT 231.310 75.390 233.290 75.440 ;
        RECT 231.260 73.410 233.340 75.390 ;
        RECT 231.310 73.360 233.290 73.410 ;
        RECT 220.750 72.300 225.700 73.300 ;
        RECT 249.050 66.900 251.050 76.950 ;
        RECT 247.050 64.900 251.050 66.900 ;
        RECT 249.050 60.300 251.050 64.900 ;
        RECT 255.400 60.300 257.400 60.350 ;
        RECT 265.750 60.300 267.750 60.350 ;
        RECT 277.450 60.300 279.450 60.350 ;
        RECT 4.000 59.550 6.000 59.600 ;
        RECT 4.000 57.550 178.700 59.550 ;
        RECT 249.050 58.300 280.200 60.300 ;
        RECT 4.000 57.500 6.000 57.550 ;
        RECT 209.450 56.350 210.550 57.350 ;
        RECT 221.800 56.750 222.900 57.750 ;
        RECT 209.500 54.500 210.500 56.350 ;
        RECT 221.850 54.550 222.850 56.750 ;
        RECT 209.000 11.600 211.000 54.500 ;
        RECT 221.350 19.600 223.350 54.550 ;
        RECT 221.350 17.600 245.500 19.600 ;
        RECT 221.100 11.600 223.100 11.650 ;
        RECT 209.000 9.600 223.100 11.600 ;
        RECT 221.100 9.550 223.100 9.600 ;
        RECT 243.500 11.150 245.500 17.600 ;
        RECT 249.050 15.450 251.050 58.300 ;
        RECT 255.400 58.250 257.400 58.300 ;
        RECT 265.750 58.250 267.750 58.300 ;
        RECT 277.450 58.250 279.450 58.300 ;
        RECT 308.250 15.450 310.250 15.500 ;
        RECT 249.050 13.450 310.250 15.450 ;
        RECT 308.250 13.400 310.250 13.450 ;
        RECT 264.900 11.150 266.900 11.200 ;
        RECT 243.500 9.150 266.900 11.150 ;
        RECT 264.900 9.100 266.900 9.150 ;
      LAYER Metal4 ;
        RECT 6.950 106.000 7.000 108.000 ;
        RECT 9.000 106.000 9.050 108.000 ;
        RECT 255.550 107.500 257.550 107.550 ;
        RECT 266.650 107.500 268.650 107.550 ;
        RECT 277.250 107.500 279.250 107.550 ;
        RECT 255.500 105.500 257.600 107.500 ;
        RECT 266.600 105.500 268.700 107.500 ;
        RECT 277.200 105.500 279.300 107.500 ;
        RECT 255.550 105.450 257.550 105.500 ;
        RECT 266.650 105.450 268.650 105.500 ;
        RECT 277.250 105.450 279.250 105.500 ;
        RECT 249.050 102.750 251.050 104.200 ;
        RECT 253.100 102.900 280.500 103.500 ;
        RECT 249.000 100.750 251.100 102.750 ;
        RECT 249.050 91.000 251.050 100.750 ;
        RECT 249.000 89.000 251.100 91.000 ;
        RECT 231.310 75.390 233.290 75.440 ;
        RECT 249.050 75.390 251.050 89.000 ;
        RECT 231.310 75.350 251.050 75.390 ;
        RECT 231.310 73.410 251.100 75.350 ;
        RECT 231.310 73.360 233.290 73.410 ;
        RECT 249.000 73.350 251.100 73.410 ;
        RECT 249.050 62.100 251.050 73.350 ;
        RECT 253.100 62.900 254.900 102.900 ;
        RECT 279.900 62.900 280.500 102.900 ;
        RECT 253.100 62.300 280.500 62.900 ;
        RECT 255.400 60.300 257.400 60.350 ;
        RECT 265.750 60.300 267.750 60.350 ;
        RECT 277.450 60.300 279.450 60.350 ;
        RECT 3.950 57.550 4.000 59.550 ;
        RECT 6.000 57.550 6.050 59.550 ;
        RECT 255.350 58.300 257.450 60.300 ;
        RECT 265.700 58.300 267.800 60.300 ;
        RECT 277.400 58.300 279.500 60.300 ;
        RECT 255.400 58.250 257.400 58.300 ;
        RECT 265.750 58.250 267.750 58.300 ;
        RECT 277.450 58.250 279.450 58.300 ;
        RECT 308.200 13.450 310.300 15.450 ;
        RECT 221.050 9.600 223.150 11.600 ;
        RECT 221.100 1.000 223.100 9.600 ;
        RECT 264.850 9.150 266.950 11.150 ;
        RECT 264.900 1.000 266.900 9.150 ;
        RECT 308.250 1.000 310.250 13.450 ;
      LAYER Metal5 ;
        RECT 255.500 105.500 257.600 107.500 ;
        RECT 266.600 105.500 268.700 107.500 ;
        RECT 277.200 105.500 279.300 107.500 ;
        RECT 249.050 102.750 251.050 102.800 ;
        RECT 253.410 102.750 253.850 103.215 ;
        RECT 249.050 100.750 253.850 102.750 ;
        RECT 255.550 102.500 257.550 105.500 ;
        RECT 266.650 102.500 268.650 105.500 ;
        RECT 277.250 102.500 279.250 105.500 ;
        RECT 249.050 100.700 251.050 100.750 ;
        RECT 249.050 91.000 251.050 91.050 ;
        RECT 253.410 91.000 253.850 100.750 ;
        RECT 249.050 89.000 253.850 91.000 ;
        RECT 249.050 88.950 251.050 89.000 ;
        RECT 249.050 75.350 251.050 75.400 ;
        RECT 253.410 75.350 253.850 89.000 ;
        RECT 249.050 73.350 253.850 75.350 ;
        RECT 249.050 73.300 251.050 73.350 ;
        RECT 253.410 65.500 253.850 73.350 ;
        RECT 249.000 63.500 253.850 65.500 ;
        RECT 253.410 62.585 253.850 63.500 ;
        RECT 255.300 63.300 279.500 102.500 ;
        RECT 255.400 60.300 257.400 63.300 ;
        RECT 265.750 60.300 267.750 63.300 ;
        RECT 277.450 60.300 279.450 63.300 ;
        RECT 255.350 58.300 257.450 60.300 ;
        RECT 265.700 58.300 267.800 60.300 ;
        RECT 277.400 58.300 279.500 60.300 ;
  END
END tt_um_aicoss_opamp
END LIBRARY

